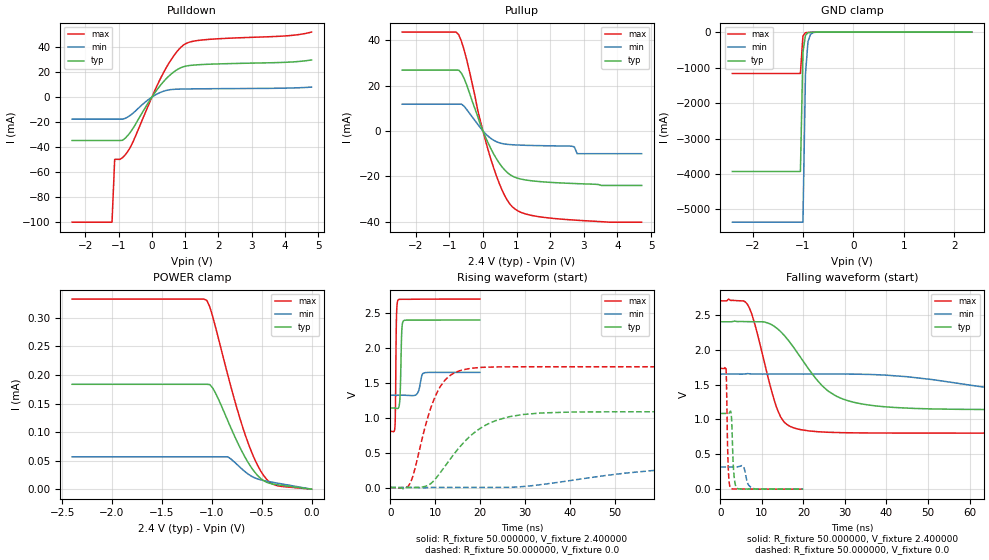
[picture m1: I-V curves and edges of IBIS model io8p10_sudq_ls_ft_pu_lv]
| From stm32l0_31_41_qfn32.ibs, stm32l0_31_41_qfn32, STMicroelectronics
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|   Model io8p10_sudq_ls_ft_pu_lv
[Model]  io8p10_sudq_ls_ft_pu_lv
Model_type I/O
Polarity   Non-Inverting
Enable   Active-Low
Vinl =   0.720000V
Vinh =   1.680000V
Vmeas =  1.200000V
Cref =   50.000000pF
Rref =   100.000000M
Vref =   0.0V
C_comp   2.317700pF   2.286600pF   2.332700pF
[Temperature Range]   25.000000   0.105000k   -40.000000
[Pullup Reference]   2.400000V   1.650000V   2.700000V
[Pulldown Reference]   0.0V   0.0V   0.0V
[POWER Clamp Reference]   2.400000V   1.650000V   2.700000V
[GND Clamp Reference]   0.0V   0.0V   0.0V
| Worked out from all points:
|   slope of the pulldown table from 0 to 0.36 V, typ, clamps not added: 28.4 ohm
|   slope of the pullup table from 0 to 0.36 V, typ, clamps not added: 32.2 ohm
|   GND clamp passes 1 mA (typ) near -0.65 V on its own axis
|   rising waveform, R_fixture 50.000000, V_fixture 2.400000: 20-80 % time 276ps typ, 631ps min, 184ps max; typ from 1.14 V to 2.4 V
|   rising waveform, R_fixture 50.000000, V_fixture 0.0: 20-80 % time 9.35ns typ, 24.7ns min, 4.82ns max; typ from 0.001 V to 1.09 V
|   falling waveform, R_fixture 50.000000, V_fixture 2.400000: 20-80 % time 10.2ns typ, 28.1ns min, 4.98ns max; typ from 2.4 V to 1.14 V
|   falling waveform, R_fixture 50.000000, V_fixture 0.0: 20-80 % time 459ps typ, 827ps min, 359ps max; typ from 1.09 V to 0.001 V
[Pulldown]
|Voltage   I(typ)   I(min)   I(max)
-2.4V     -34.71mA   -17.62mA   -100mA
-1.2V     -34.71mA   -17.62mA   -100mA
-1.12V    -34.71mA   -17.62mA   -49.77mA
-960mV    -34.71mA   -17.62mA   -49.77mA
-720mV    -30.52mA   -15.81mA   -43.24mA
-560mV    -24.66mA   -12.69mA   -35.31mA
-80mV     -3.3mA     -1.497mA   -4.982mA
320mV     11.47mA    4.39mA     18.08mA
640mV     19.72mA    6.139mA    32.34mA
960mV     24.33mA    6.432mA    41.77mA
1.52V     26.01mA    6.613mA    45.64mA
4.8V      29.64mA    7.944mA    51.92mA
[Pullup]
|Voltage   I(typ)   I(min)   I(max)
-2.4V     26.83mA    11.83mA    43.61mA
-800mV    26.83mA    11.83mA    43.61mA
-720mV    26.83mA    11.83mA    42.44mA
-480mV    20.19mA    9.416mA    31.24mA
-80mV     3.011mA    1.512mA    4.671mA
320mV     -10.16mA   -4.078mA   -16.34mA
640mV     -17.08mA   -5.718mA   -28.28mA
960mV     -20.45mA   -6.129mA   -34.49mA
2V        -22.64mA   -6.529mA   -38.4mA
2.72V     -23.16mA   -7mA       -39.27mA
2.8V      -23.2mA    -10mA      -39.35mA
4.72V     -24mA      -10mA      -40.2mA
[GND_clamp]
|Voltage   I(typ)   I(min)   I(max)
-2.4V     -3.929A    -5.359A    -1.166A
-1.05V    -3.929A    -5.359A    -1.166A
-1V       -574.5mA   -5.359A    -109.1mA
-950mV    -90.02mA   -1.192A    -18.55mA
-900mV    -18.41mA   -269.7mA   -9.049mA
-850mV    -6.764mA   -63.59mA   -6.579mA
-800mV    -4.027mA   -16.66mA   -4.859mA
-650mV    -1.043mA   -1.218mA   -1.146mA
2.35V     0A         0A         0A
[POWER_clamp]
|Voltage   I(typ)   I(min)   I(max)
-2.4V     183.7uA    56.67uA    333uA
-1.05V    183.7uA    56.67uA    330.8uA
-1.02V    183.2uA    56.67uA    319.3uA
-960mV    167.4uA    56.67uA    282.2uA
-840mV    120.1uA    56.67uA    200.3uA
-750mV    84.75uA    43.78uA    142.9uA
-690mV    63.55uA    34.11uA    108.5uA
-600mV    37.04uA    22.44uA    64.62uA
-510mV    18.73uA    16.34uA    31.91uA
-450mV    12.06uA    14.02uA    17.25uA
-360mV    8.154uA    11.11uA    6.782uA
0V        0A         0A         0A
[Ramp]
| variable   typ   min   max
dV/dt_r  0.65095/9.34277n   0.19037/24.71546n   1.03799/4.81256n
dV/dt_f  0.75624/10.16071n   0.19656/28.10235n   1.13750/4.97000n
R_load = 50.000000
[Rising Waveform]
R_fixture= 50.000000
V_fixture= 2.400000
V_fixture_min= 1.650000
V_fixture_max= 2.700000
|time   V(typ)   V(min)   V(max)
0s        1.14V      1.322V     804.2mV
1.041ns   1.139V     1.322V     870.9mV
1.161ns   1.138V     1.322V     1.192V
1.361ns   1.135V     1.322V     2.389V
1.722ns   1.134V     1.322V     2.685V
2.162ns   1.291V     1.323V     2.696V
2.563ns   2.248V     1.323V     2.697V
2.923ns   2.386V     1.323V     2.697V
7.608ns   2.399V     1.643V     2.699V
19.94ns   2.4V       1.65V      2.7V
[Rising Waveform]
R_fixture= 50.000000
V_fixture= 0.0
V_fixture_min= 0.0
V_fixture_max= 0.0
|time   V(typ)   V(min)   V(max)
0s        880.2uV    1.328mV    514.1uV
4.505ns   1.763mV    1.424mV    71.49mV
8.509ns   38.25mV    1.618mV    1.039V
11.51ns   246.5mV    2.319mV    1.482V
14.01ns   466mV      2.316mV    1.634V
18.02ns   750.1mV    2.326mV    1.709V
26.53ns   1.015V     4.262mV    1.729V
40.54ns   1.082V     105.1mV    1.73V
86.09ns   1.086V     309.9mV    1.73V
249.2ns   1.086V     318.6mV    1.73V
[Falling Waveform]
R_fixture= 50.000000
V_fixture= 2.400000
V_fixture_min= 1.650000
V_fixture_max= 2.700000
|time   V(typ)   V(min)   V(max)
0s        2.4V       1.65V      2.7V
6.507ns   2.402V     1.657V     2.649V
8.008ns   2.401V     1.651V     2.424V
12.51ns   2.351V     1.65V      1.369V
14.51ns   2.259V     1.65V      1.036V
21.52ns   1.701V     1.65V      834mV
29.53ns   1.292V     1.65V      810.2mV
46.05ns   1.159V     1.605V     804.4mV
97.1ns    1.14V      1.346V     804.2mV
249.2ns   1.14V      1.322V     804.2mV
[Falling Waveform]
R_fixture= 50.000000
V_fixture= 0.0
V_fixture_min= 0.0
V_fixture_max= 0.0
|time   V(typ)   V(min)   V(max)
0s        1.086V     318.6mV    1.73V
1.321ns   1.086V     318.6mV    1.745V
1.441ns   1.086V     318.6mV    1.586V
1.882ns   1.085V     318.6mV    327.6mV
2.442ns   1.119V     318.6mV    19.33mV
2.683ns   1.015V     318.6mV    7.989mV
3.203ns   250.2mV    318.4mV    3.317mV
3.884ns   18.75mV    318.2mV    3.12mV
7.928ns   2.732mV    9.664mV    2.169mV
19.94ns   880.2uV    1.328mV    514.1uV
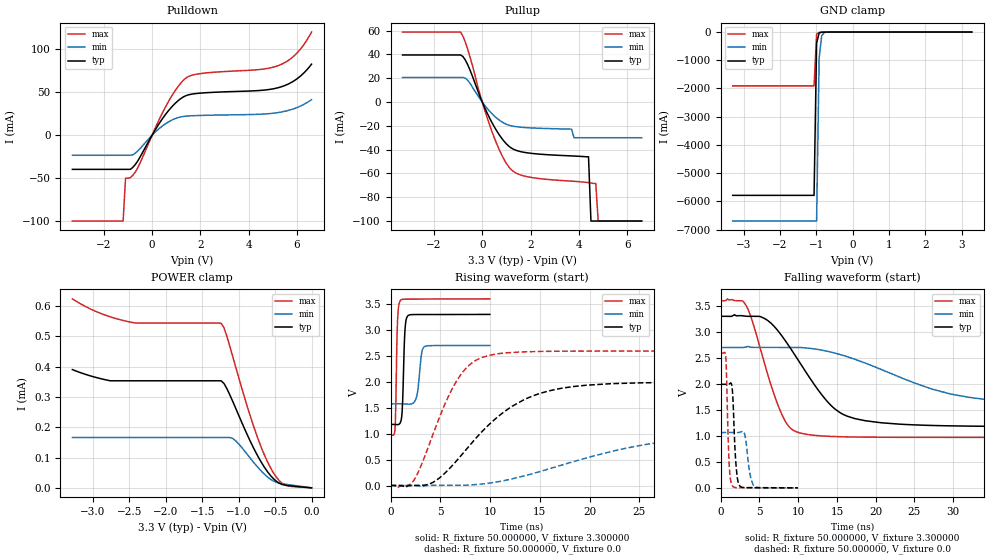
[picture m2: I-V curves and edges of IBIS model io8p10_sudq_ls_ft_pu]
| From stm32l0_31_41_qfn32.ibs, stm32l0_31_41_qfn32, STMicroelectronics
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|   Model io8p10_sudq_ls_ft_pu
[Model]  io8p10_sudq_ls_ft_pu
Model_type I/O
Polarity   Non-Inverting
Enable   Active-Low
Vinl =   0.990000V
Vinh =   2.310000V
Vmeas =  1.650000V
Cref =   50.000000pF
Rref =   100.000000M
Vref =   0.0V
C_comp   2.343000pF   2.309800pF   2.393900pF
[Temperature Range]   25.000000   0.125000k   -40.000000
[Pullup Reference]   3.300000V   2.700000V   3.600000V
[Pulldown Reference]   0.0V   0.0V   0.0V
[POWER Clamp Reference]   3.300000V   2.700000V   3.600000V
[GND Clamp Reference]   0.0V   0.0V   0.0V
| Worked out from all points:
|   slope of the pulldown table from 0 to 0.495 V, typ, clamps not added: 22.6 ohm
|   slope of the pullup table from 0 to 0.495 V, typ, clamps not added: 23.9 ohm
|   GND clamp passes 1 mA (typ) near -0.64 V on its own axis
|   rising waveform, R_fixture 50.000000, V_fixture 3.300000: 20-80 % time 207ps typ, 359ps min, 164ps max; typ from 1.18 V to 3.3 V
|   rising waveform, R_fixture 50.000000, V_fixture 0.0: 20-80 % time 6.56ns typ, 13.7ns min, 3.48ns max; typ from 0.001 V to 1.99 V
|   falling waveform, R_fixture 50.000000, V_fixture 3.300000: 20-80 % time 6.01ns typ, 12.6ns min, 3.3ns max; typ from 3.3 V to 1.18 V
|   falling waveform, R_fixture 50.000000, V_fixture 0.0: 20-80 % time 386ps typ, 554ps min, 307ps max; typ from 1.99 V to 0.001 V
[Pulldown]
|Voltage   I(typ)   I(min)   I(max)
-3.3V     -39.8mA    -23.38mA   -100mA
-1.2V     -39.8mA    -23.38mA   -100mA
-1.1V     -39.8mA    -23.38mA   -50.11mA
-900mV    -39.8mA    -23.38mA   -49.43mA
-700mV    -34.25mA   -21mA      -43.13mA
600mV     25.84mA    14.18mA    35.34mA
1V        38.32mA    19.82mA    53.81mA
1.4V      46.09mA    22.19mA    66.63mA
2V        49.05mA    23.02mA    71.83mA
5.2V      55.23mA    26.32mA    80.92mA
6V        65.77mA    32.26mA    95.84mA
6.6V      82.81mA    41.44mA    120.2mA
[Pullup]
|Voltage   I(typ)   I(min)   I(max)
-3.3V     39.53mA    20.64mA    58.82mA
-900mV    39.53mA    20.64mA    58.82mA
-600mV    31.26mA    18.2mA     44.19mA
500mV     -20.88mA   -11.78mA   -30.07mA
1.3V      -39.75mA   -20.41mA   -58.47mA
3.7V      -45.29mA   -22.8mA    -66.51mA
3.8V      -45.39mA   -30mA      -66.64mA
4.4V      -46.01mA   -30mA      -67.77mA
4.5V      -100mA     -30mA      -68.06mA
4.7V      -100mA     -30mA      -68.41mA
4.8V      -100mA     -30mA      -100mA
6.6V      -100mA     -30mA      -100mA
[GND_clamp]
|Voltage   I(typ)   I(min)   I(max)
-3.3V     -5.787A    -6.696A    -1.906A
-1.06V    -5.787A    -6.696A    -1.906A
-990mV    -393.4mA   -6.696A    -70.75mA
-920mV    -33.02mA   -919.4mA   -10.9mA
-850mV    -6.829mA   -131.3mA   -6.521mA
-780mV    -3.478mA   -21.06mA   -4.208mA
3.28V     0A         0A         0A
[POWER_clamp]
|Voltage   I(typ)   I(min)   I(max)
-3.28V    390.5uA    166.4uA    624.1uA
-2.76V    353.6uA    166.4uA    564.6uA
-2.44V    353.6uA    166.4uA    545.3uA
-1.24V    353.6uA    166.4uA    543.5uA
-1.2V     344.2uA    166.4uA    528.2uA
-1.16V    327.1uA    166.4uA    499.5uA
-1.04V    262.6uA    155.2uA    398.8uA
-760mV    115.1uA    74.4uA     179.3uA
-560mV    39.86uA    27.94uA    65.07uA
-440mV    15uA       15.53uA    23.15uA
-360mV    8.745uA    12.05uA    9.089uA
0V        0A         0A         0A
[Ramp]
| variable   typ   min   max
dV/dt_r  1.19492/6.55742n   0.62951/13.61414n   1.55547/3.47399n
dV/dt_f  1.27284/5.99927n   0.65196/12.47769n   1.57747/3.29253n
R_load = 50.000000
[Rising Waveform]
R_fixture= 50.000000
V_fixture= 3.300000
V_fixture_min= 2.700000
V_fixture_max= 3.600000
|time   V(typ)   V(min)   V(max)
0s        1.178V     1.575V     970.8mV
440.4ps   1.177V     1.575V     1.078V
700.7ps   1.174V     1.575V     3.174V
981ps     1.214V     1.575V     3.568V
1.181ns   1.499V     1.575V     3.59V
1.441ns   2.981V     1.574V     3.594V
1.722ns   3.271V     1.57V      3.595V
2.603ns   3.298V     1.703V     3.595V
3.363ns   3.298V     2.673V     3.597V
9.97ns    3.3V       2.7V       3.6V
[Rising Waveform]
R_fixture= 50.000000
V_fixture= 0.0
V_fixture_min= 0.0
V_fixture_max= 0.0
|time   V(typ)   V(min)   V(max)
0s        1.061mV    1.811mV    1.023mV
2.302ns   1.603mV    150.3uV    90.14mV
4.204ns   54.66mV    3.606mV    957mV
6.607ns   471.9mV    4.043mV    2.008V
8.108ns   809.6mV    11.17mV    2.355V
9.91ns    1.178V     44.9mV     2.511V
13.81ns   1.691V     205.7mV    2.58V
18.42ns   1.91V      463.2mV    2.591V
31.03ns   1.99V      929.9mV    2.593V
49.85ns   1.993V     1.064V     2.593V
[Falling Waveform]
R_fixture= 50.000000
V_fixture= 3.300000
V_fixture_min= 2.700000
V_fixture_max= 3.600000
|time   V(typ)   V(min)   V(max)
0s        3.3V       2.7V       3.6V
3.303ns   3.301V     2.711V     3.503V
5.606ns   3.262V     2.702V     2.421V
7.508ns   2.999V     2.702V     1.55V
8.709ns   2.751V     2.701V     1.198V
9.91ns    2.479V     2.701V     1.071V
14.21ns   1.59V      2.613V     990.4mV
17.32ns   1.333V     2.475V     978.7mV
29.83ns   1.193V     1.802V     971.2mV
49.85ns   1.178V     1.575V     970.8mV
[Falling Waveform]
R_fixture= 50.000000
V_fixture= 0.0
V_fixture_min= 0.0
V_fixture_max= 0.0
|time   V(typ)   V(min)   V(max)
0s        1.993V     1.064V     2.593V
660.7ps   1.992V     1.064V     2.504V
1.081ns   1.997V     1.064V     503.3mV
1.481ns   1.915V     1.064V     44.82mV
1.962ns   471.2mV    1.064V     6.714mV
2.442ns   42.84mV    1.068V     5.019mV
3.103ns   4.738mV    1.026V     5.101mV
3.764ns   3.865mV    278.3mV    5.042mV
4.404ns   3.916mV    23.69mV    3.705mV
9.97ns    1.061mV    1.811mV    1.023mV
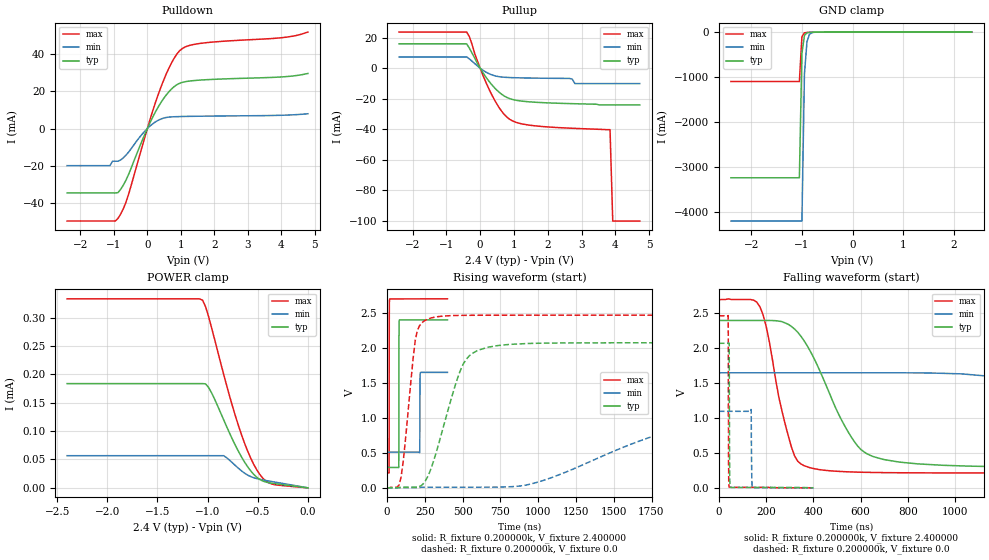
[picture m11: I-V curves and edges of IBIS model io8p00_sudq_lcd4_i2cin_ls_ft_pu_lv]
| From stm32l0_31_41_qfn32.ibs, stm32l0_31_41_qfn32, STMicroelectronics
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|   Model io8p00_sudq_lcd4_i2cin_ls_ft_pu_lv
[Model]  io8p00_sudq_lcd4_i2cin_ls_ft_pu_lv
Model_type I/O
Polarity   Non-Inverting
Enable   Active-Low
Vinl =   0.720000V
Vinh =   1.680000V
Vmeas =  1.200000V
Cref =   50.000000pF
Rref =   100.000000M
Vref =   0.0V
C_comp   2.470900pF   2.435200pF   2.490500pF
[Temperature Range]   25.000000   0.105000k   -40.000000
[Pullup Reference]   2.400000V   1.650000V   2.700000V
[Pulldown Reference]   0.0V   0.0V   0.0V
[POWER Clamp Reference]   2.400000V   1.650000V   2.700000V
[GND Clamp Reference]   0.0V   0.0V   0.0V
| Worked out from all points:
|   slope of the pulldown table from 0 to 0.36 V, typ, clamps not added: 28.5 ohm
|   slope of the pullup table from 0 to 0.36 V, typ, clamps not added: 32.2 ohm
|   GND clamp passes 1 mA (typ) near -0.64 V on its own axis
|   rising waveform, R_fixture 0.200000k, V_fixture 2.400000: 20-80 % time 673ps typ, 854ps min, 738ps max; typ from 0.292 V to 2.4 V
|   rising waveform, R_fixture 0.200000k, V_fixture 0.0: 20-80 % time 169ns typ, 818ns min, 66.7ns max; typ from 0.001 V to 2.07 V
|   falling waveform, R_fixture 0.200000k, V_fixture 2.400000: 20-80 % time 180ns typ, 729ns min, 89.7ns max; typ from 2.4 V to 0.292 V
|   falling waveform, R_fixture 0.200000k, V_fixture 0.0: 20-80 % time 1.16ns typ, 1.67ns min, 952ps max; typ from 2.07 V to 0.001 V
[Pulldown]
|Voltage   I(typ)   I(min)   I(max)
-2.4V     -34.71mA   -20mA      -49.82mA
-1.12V    -34.71mA   -20mA      -49.82mA
-1.04V    -34.71mA   -17.6mA    -49.82mA
-880mV    -34.55mA   -17.6mA    -48.46mA
-560mV    -24.65mA   -12.68mA   -35.33mA
0V        0A         0A         0A
400mV     13.84mA    5.066mA    22.03mA
720mV     21.25mA    6.254mA    35.26mA
1.04V     24.83mA    6.464mA    43.02mA
1.6V      26.11mA    6.627mA    45.88mA
4V        27.76mA    7.125mA    48.87mA
4.8V      29.64mA    7.94mA     51.96mA
[Pullup]
|Voltage   I(typ)   I(min)   I(max)
-2.4V     16.03mA    7.415mA    23.74mA
-400mV    16.03mA    7.415mA    23.74mA
80mV      -2.838mA   -1.261mA   -4.478mA
320mV     -10.16mA   -4.078mA   -16.34mA
640mV     -17.08mA   -5.718mA   -28.28mA
960mV     -20.45mA   -6.128mA   -34.49mA
1.76V     -22.39mA   -6.47mA    -37.97mA
2.64V     -23.11mA   -6.64mA    -39.19mA
2.8V      -23.2mA    -10mA      -39.35mA
3.84V     -24mA      -10mA      -40.2mA
3.92V     -24mA      -10mA      -100mA
4.72V     -24mA      -10mA      -100mA
[GND_clamp]
|Voltage   I(typ)   I(min)   I(max)
-2.4V     -3.237A    -4.197A    -1.1A
-1.05V    -3.237A    -4.197A    -1.1A
-1V       -475.5mA   -4.197A    -104.1mA
-950mV    -76.08mA   -935.1mA   -18.44mA
-900mV    -16.57mA   -212.6mA   -9.263mA
-850mV    -6.62mA    -50.88mA   -6.764mA
-800mV    -4.092mA   -13.84mA   -4.994mA
-650mV    -1.07mA    -1.21mA    -1.175mA
2.35V     0A         0A         0A
[POWER_clamp]
|Voltage   I(typ)   I(min)   I(max)
-2.4V     183.7uA    56.67uA    333uA
-1.05V    183.7uA    56.67uA    330.8uA
-1.02V    183.2uA    56.67uA    319.3uA
-960mV    167.4uA    56.67uA    282.2uA
-840mV    120.1uA    56.67uA    200.3uA
-750mV    84.75uA    43.78uA    142.9uA
-690mV    63.55uA    34.11uA    108.5uA
-600mV    37.04uA    22.45uA    64.63uA
-510mV    18.73uA    16.35uA    31.91uA
-450mV    12.06uA    14.02uA    17.25uA
-360mV    8.154uA    11.11uA    6.782uA
0V        0A         0A         0A
[Ramp]
| variable   typ   min   max
dV/dt_r  0.65095/0.30170u   0.19035/0.81532u   1.03799/0.14355u
dV/dt_f  0.75618/0.32145u   0.19644/0.84584u   1.13779/0.15968u
R_load = 50.000000
[Rising Waveform]
R_fixture= 0.200000k
V_fixture= 2.400000
V_fixture_min= 1.650000
V_fixture_max= 2.700000
|time   V(typ)   V(min)   V(max)
0s        292mV      510.8mV    213.5mV
14.01ns   292mV      510.8mV    220.7mV
15.22ns   292mV      510.8mV    2.446V
17.22ns   292mV      510.8mV    2.696V
77.68ns   290.2mV    510.8mV    2.7V
79.28ns   2.091V     510.8mV    2.7V
81.28ns   2.395V     510.8mV    2.7V
216.2ns   2.4V       506mV      2.7V
221ns     2.4V       1.647V     2.7V
400ns     2.4V       1.65V      2.7V
[Rising Waveform]
R_fixture= 0.200000k
V_fixture= 0.0
V_fixture_min= 0.0
V_fixture_max= 0.0
|time   V(typ)   V(min)   V(max)
0s        1.171mV    2.207mV    629.1uV
93.43ns   10.52mV    2.207mV    157.3mV
200.2ns   12.24mV    2.207mV    2.244V
280.3ns   214.1mV    9.997mV    2.419V
373.7ns   877.8mV    9.997mV    2.454V
547.2ns   1.891V     10.04mV    2.465V
934.3ns   2.063V     47.01mV    2.467V
1.989us   2.073V     875mV      2.467V
2.789us   2.073V     1.064V     2.467V
13.33us   2.073V     1.097V     2.467V
[Falling Waveform]
R_fixture= 0.200000k
V_fixture= 2.400000
V_fixture_min= 1.650000
V_fixture_max= 2.700000
|time   V(typ)   V(min)   V(max)
0s        2.4V       1.65V      2.7V
173.5ns   2.4V       1.65V      2.597V
320.3ns   2.277V     1.65V      459.2mV
493.8ns   1.149V     1.65V      239.2mV
600.6ns   551.6mV    1.65V      224.5mV
774.1ns   366.4mV    1.649V     216.9mV
1.308us   299.5mV    1.524V     213.7mV
2.202us   292.2mV    723.9mV    213.5mV
2.829us   292mV      567.8mV    213.5mV
13.33us   292mV      510.8mV    213.5mV
[Falling Waveform]
R_fixture= 0.200000k
V_fixture= 0.0
V_fixture_min= 0.0
V_fixture_max= 0.0
|time   V(typ)   V(min)   V(max)
0s        2.073V     1.097V     2.467V
39.24ns   2.073V     1.097V     2.471V
40.84ns   2.073V     1.097V     376.1mV
43.64ns   2.071V     1.097V     11.57mV
45.25ns   363.1mV    1.097V     8.932mV
48.05ns   10.72mV    1.097V     8.574mV
136.5ns   6.58mV     1.123V     8.3mV
138.9ns   6.58mV     204.1mV    8.261mV
142.9ns   6.58mV     5.249mV    8.195mV
400ns     1.171mV    2.207mV    629.1uV
